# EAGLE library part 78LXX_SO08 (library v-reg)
VOLTAGE REGULATOR IMax: 100mA

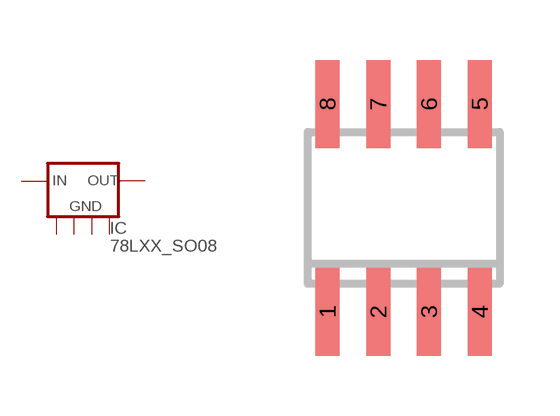
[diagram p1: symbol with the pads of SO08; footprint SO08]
Designator prefix IC

## 78LXX_SO08  [SO08]
1  OUT  pas
2  GND3  in
3  GND2  in
6  GND1  in
7  GND  in
8  IN  in

## Footprint SO08 (pad centres in mm)
smd 0.6 x 2.2: 1 -1.905,-2.6; 2 -0.635,-2.6; 3 0.635,-2.6; 4 1.905,-2.6; 5 1.905,2.6; 6 0.635,2.6; 7 -0.635,2.6; 8 -1.905,2.6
